VERSION 5.7 ;
  NOWIREEXTENSIONATPIN ON ;
  DIVIDERCHAR "/" ;
  BUSBITCHARS "[]" ;
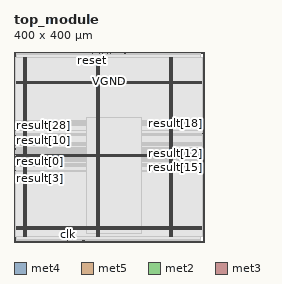
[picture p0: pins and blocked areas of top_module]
MACRO top_module
  CLASS BLOCK ;
  FOREIGN top_module ;
  ORIGIN 0.000 0.000 ;
  SIZE 400.000 BY 400.000 ;
  PIN VGND
    DIRECTION INOUT ;
    USE GROUND ;
    PORT
      LAYER met4 ;
        RECT 24.340 10.640 25.940 389.200 ;
    END
    PORT
      LAYER met4 ;
        RECT 177.940 10.640 179.540 389.200 ;
    END
    PORT
      LAYER met4 ;
        RECT 331.540 10.640 333.140 389.200 ;
    END
    PORT
      LAYER met5 ;
        RECT 5.280 30.030 394.460 31.630 ;
    END
    PORT
      LAYER met5 ;
        RECT 5.280 183.210 394.460 184.810 ;
    END
    PORT
      LAYER met5 ;
        RECT 5.280 336.390 394.460 337.990 ;
    END
  END VGND
  PIN VPWR
    DIRECTION INOUT ;
    USE POWER ;
    PORT
      LAYER met4 ;
        RECT 21.040 10.640 22.640 389.200 ;
    END
    PORT
      LAYER met4 ;
        RECT 174.640 10.640 176.240 389.200 ;
    END
    PORT
      LAYER met4 ;
        RECT 328.240 10.640 329.840 389.200 ;
    END
    PORT
      LAYER met5 ;
        RECT 5.280 26.730 394.460 28.330 ;
    END
    PORT
      LAYER met5 ;
        RECT 5.280 179.910 394.460 181.510 ;
    END
    PORT
      LAYER met5 ;
        RECT 5.280 333.090 394.460 334.690 ;
    END
  END VPWR
  PIN clk
    DIRECTION INPUT ;
    USE SIGNAL ;
    ANTENNAGATEAREA 0.852000 ;
    PORT
      LAYER met2 ;
        RECT 112.790 0.000 113.070 4.000 ;
    END
  END clk
  PIN control
    DIRECTION INPUT ;
    USE SIGNAL ;
    ANTENNAGATEAREA 0.742500 ;
    PORT
      LAYER met2 ;
        RECT 148.210 0.000 148.490 4.000 ;
    END
  END control
  PIN reset
    DIRECTION INPUT ;
    USE SIGNAL ;
    ANTENNAGATEAREA 0.213000 ;
    ANTENNADIFFAREA 0.434700 ;
    PORT
      LAYER met2 ;
        RECT 164.310 396.000 164.590 400.000 ;
    END
  END reset
  PIN result[0]
    DIRECTION OUTPUT ;
    USE SIGNAL ;
    ANTENNADIFFAREA 0.445500 ;
    PORT
      LAYER met3 ;
        RECT 0.000 170.040 4.000 170.640 ;
    END
  END result[0]
  PIN result[10]
    DIRECTION OUTPUT ;
    USE SIGNAL ;
    ANTENNADIFFAREA 0.445500 ;
    PORT
      LAYER met3 ;
        RECT 0.000 197.240 4.000 197.840 ;
    END
  END result[10]
  PIN result[11]
    DIRECTION OUTPUT ;
    USE SIGNAL ;
    ANTENNADIFFAREA 0.445500 ;
    PORT
      LAYER met3 ;
        RECT 0.000 183.640 4.000 184.240 ;
    END
  END result[11]
  PIN result[12]
    DIRECTION OUTPUT ;
    USE SIGNAL ;
    ANTENNADIFFAREA 0.445500 ;
    PORT
      LAYER met3 ;
        RECT 396.000 187.040 400.000 187.640 ;
    END
  END result[12]
  PIN result[13]
    DIRECTION OUTPUT ;
    USE SIGNAL ;
    ANTENNADIFFAREA 0.445500 ;
    PORT
      LAYER met3 ;
        RECT 396.000 190.440 400.000 191.040 ;
    END
  END result[13]
  PIN result[14]
    DIRECTION OUTPUT ;
    USE SIGNAL ;
    ANTENNADIFFAREA 0.445500 ;
    PORT
      LAYER met3 ;
        RECT 396.000 180.240 400.000 180.840 ;
    END
  END result[14]
  PIN result[15]
    DIRECTION OUTPUT ;
    USE SIGNAL ;
    ANTENNADIFFAREA 0.445500 ;
    PORT
      LAYER met3 ;
        RECT 396.000 173.440 400.000 174.040 ;
    END
  END result[15]
  PIN result[16]
    DIRECTION OUTPUT ;
    USE SIGNAL ;
    ANTENNADIFFAREA 0.445500 ;
    PORT
      LAYER met3 ;
        RECT 396.000 183.640 400.000 184.240 ;
    END
  END result[16]
  PIN result[17]
    DIRECTION OUTPUT ;
    USE SIGNAL ;
    ANTENNADIFFAREA 0.445500 ;
    PORT
      LAYER met3 ;
        RECT 396.000 176.840 400.000 177.440 ;
    END
  END result[17]
  PIN result[18]
    DIRECTION OUTPUT ;
    USE SIGNAL ;
    ANTENNADIFFAREA 0.445500 ;
    PORT
      LAYER met3 ;
        RECT 396.000 248.240 400.000 248.840 ;
    END
  END result[18]
  PIN result[19]
    DIRECTION OUTPUT ;
    USE SIGNAL ;
    ANTENNADIFFAREA 0.445500 ;
    PORT
      LAYER met3 ;
        RECT 396.000 251.640 400.000 252.240 ;
    END
  END result[19]
  PIN result[1]
    DIRECTION OUTPUT ;
    USE SIGNAL ;
    ANTENNADIFFAREA 0.445500 ;
    PORT
      LAYER met2 ;
        RECT 144.990 0.000 145.270 4.000 ;
    END
  END result[1]
  PIN result[20]
    DIRECTION OUTPUT ;
    USE SIGNAL ;
    ANTENNADIFFAREA 0.445500 ;
    PORT
      LAYER met3 ;
        RECT 396.000 255.040 400.000 255.640 ;
    END
  END result[20]
  PIN result[21]
    DIRECTION OUTPUT ;
    USE SIGNAL ;
    ANTENNADIFFAREA 0.445500 ;
    PORT
      LAYER met3 ;
        RECT 396.000 227.840 400.000 228.440 ;
    END
  END result[21]
  PIN result[22]
    DIRECTION OUTPUT ;
    USE SIGNAL ;
    ANTENNADIFFAREA 0.795200 ;
    PORT
      LAYER met2 ;
        RECT 231.930 396.000 232.210 400.000 ;
    END
  END result[22]
  PIN result[23]
    DIRECTION OUTPUT ;
    USE SIGNAL ;
    ANTENNADIFFAREA 0.795200 ;
    PORT
      LAYER met2 ;
        RECT 235.150 396.000 235.430 400.000 ;
    END
  END result[23]
  PIN result[24]
    DIRECTION OUTPUT ;
    USE SIGNAL ;
    ANTENNADIFFAREA 0.795200 ;
    PORT
      LAYER met2 ;
        RECT 196.510 396.000 196.790 400.000 ;
    END
  END result[24]
  PIN result[25]
    DIRECTION OUTPUT ;
    USE SIGNAL ;
    ANTENNADIFFAREA 0.795200 ;
    PORT
      LAYER met2 ;
        RECT 202.950 396.000 203.230 400.000 ;
    END
  END result[25]
  PIN result[26]
    DIRECTION OUTPUT ;
    USE SIGNAL ;
    ANTENNADIFFAREA 0.795200 ;
    PORT
      LAYER met2 ;
        RECT 186.850 396.000 187.130 400.000 ;
    END
  END result[26]
  PIN result[27]
    DIRECTION OUTPUT ;
    USE SIGNAL ;
    ANTENNADIFFAREA 0.795200 ;
    PORT
      LAYER met2 ;
        RECT 180.410 396.000 180.690 400.000 ;
    END
  END result[27]
  PIN result[28]
    DIRECTION OUTPUT ;
    USE SIGNAL ;
    ANTENNADIFFAREA 0.445500 ;
    PORT
      LAYER met3 ;
        RECT 0.000 244.840 4.000 245.440 ;
    END
  END result[28]
  PIN result[29]
    DIRECTION OUTPUT ;
    USE SIGNAL ;
    ANTENNADIFFAREA 1.336500 ;
    PORT
      LAYER met3 ;
        RECT 0.000 251.640 4.000 252.240 ;
    END
  END result[29]
  PIN result[2]
    DIRECTION OUTPUT ;
    USE SIGNAL ;
    ANTENNADIFFAREA 0.445500 ;
    PORT
      LAYER met3 ;
        RECT 0.000 159.840 4.000 160.440 ;
    END
  END result[2]
  PIN result[30]
    DIRECTION OUTPUT ;
    USE SIGNAL ;
    ANTENNADIFFAREA 0.445500 ;
    PORT
      LAYER met3 ;
        RECT 0.000 234.640 4.000 235.240 ;
    END
  END result[30]
  PIN result[31]
    DIRECTION OUTPUT ;
    USE SIGNAL ;
    ANTENNADIFFAREA 1.782000 ;
    PORT
      LAYER met3 ;
        RECT 0.000 224.440 4.000 225.040 ;
    END
  END result[31]
  PIN result[3]
    DIRECTION OUTPUT ;
    USE SIGNAL ;
    ANTENNADIFFAREA 0.445500 ;
    PORT
      LAYER met3 ;
        RECT 0.000 149.640 4.000 150.240 ;
    END
  END result[3]
  PIN result[4]
    DIRECTION OUTPUT ;
    USE SIGNAL ;
    ANTENNADIFFAREA 0.445500 ;
    PORT
      LAYER met3 ;
        RECT 0.000 163.240 4.000 163.840 ;
    END
  END result[4]
  PIN result[5]
    DIRECTION OUTPUT ;
    USE SIGNAL ;
    ANTENNADIFFAREA 0.445500 ;
    PORT
      LAYER met3 ;
        RECT 0.000 180.240 4.000 180.840 ;
    END
  END result[5]
  PIN result[6]
    DIRECTION OUTPUT ;
    USE SIGNAL ;
    ANTENNADIFFAREA 0.445500 ;
    PORT
      LAYER met3 ;
        RECT 0.000 176.840 4.000 177.440 ;
    END
  END result[6]
  PIN result[7]
    DIRECTION OUTPUT ;
    USE SIGNAL ;
    ANTENNADIFFAREA 0.445500 ;
    PORT
      LAYER met3 ;
        RECT 0.000 193.840 4.000 194.440 ;
    END
  END result[7]
  PIN result[8]
    DIRECTION OUTPUT ;
    USE SIGNAL ;
    ANTENNADIFFAREA 0.445500 ;
    PORT
      LAYER met3 ;
        RECT 0.000 207.440 4.000 208.040 ;
    END
  END result[8]
  PIN result[9]
    DIRECTION OUTPUT ;
    USE SIGNAL ;
    ANTENNADIFFAREA 0.445500 ;
    PORT
      LAYER met3 ;
        RECT 0.000 204.040 4.000 204.640 ;
    END
  END result[9]
  OBS
      LAYER nwell ;
        RECT 5.330 10.795 394.410 389.150 ;
      LAYER li1 ;
        RECT 5.520 10.795 394.220 389.045 ;
      LAYER met1 ;
        RECT 4.210 10.640 394.220 389.200 ;
      LAYER met2 ;
        RECT 4.230 395.720 164.030 396.000 ;
        RECT 164.870 395.720 180.130 396.000 ;
        RECT 180.970 395.720 186.570 396.000 ;
        RECT 187.410 395.720 196.230 396.000 ;
        RECT 197.070 395.720 202.670 396.000 ;
        RECT 203.510 395.720 231.650 396.000 ;
        RECT 232.490 395.720 234.870 396.000 ;
        RECT 235.710 395.720 392.290 396.000 ;
        RECT 4.230 4.280 392.290 395.720 ;
        RECT 4.230 4.000 112.510 4.280 ;
        RECT 113.350 4.000 144.710 4.280 ;
        RECT 145.550 4.000 147.930 4.280 ;
        RECT 148.770 4.000 392.290 4.280 ;
      LAYER met3 ;
        RECT 3.990 256.040 396.000 389.125 ;
        RECT 3.990 254.640 395.600 256.040 ;
        RECT 3.990 252.640 396.000 254.640 ;
        RECT 4.400 251.240 395.600 252.640 ;
        RECT 3.990 249.240 396.000 251.240 ;
        RECT 3.990 247.840 395.600 249.240 ;
        RECT 3.990 245.840 396.000 247.840 ;
        RECT 4.400 244.440 396.000 245.840 ;
        RECT 3.990 235.640 396.000 244.440 ;
        RECT 4.400 234.240 396.000 235.640 ;
        RECT 3.990 228.840 396.000 234.240 ;
        RECT 3.990 227.440 395.600 228.840 ;
        RECT 3.990 225.440 396.000 227.440 ;
        RECT 4.400 224.040 396.000 225.440 ;
        RECT 3.990 208.440 396.000 224.040 ;
        RECT 4.400 207.040 396.000 208.440 ;
        RECT 3.990 205.040 396.000 207.040 ;
        RECT 4.400 203.640 396.000 205.040 ;
        RECT 3.990 198.240 396.000 203.640 ;
        RECT 4.400 196.840 396.000 198.240 ;
        RECT 3.990 194.840 396.000 196.840 ;
        RECT 4.400 193.440 396.000 194.840 ;
        RECT 3.990 191.440 396.000 193.440 ;
        RECT 3.990 190.040 395.600 191.440 ;
        RECT 3.990 188.040 396.000 190.040 ;
        RECT 3.990 186.640 395.600 188.040 ;
        RECT 3.990 184.640 396.000 186.640 ;
        RECT 4.400 183.240 395.600 184.640 ;
        RECT 3.990 181.240 396.000 183.240 ;
        RECT 4.400 179.840 395.600 181.240 ;
        RECT 3.990 177.840 396.000 179.840 ;
        RECT 4.400 176.440 395.600 177.840 ;
        RECT 3.990 174.440 396.000 176.440 ;
        RECT 3.990 173.040 395.600 174.440 ;
        RECT 3.990 171.040 396.000 173.040 ;
        RECT 4.400 169.640 396.000 171.040 ;
        RECT 3.990 164.240 396.000 169.640 ;
        RECT 4.400 162.840 396.000 164.240 ;
        RECT 3.990 160.840 396.000 162.840 ;
        RECT 4.400 159.440 396.000 160.840 ;
        RECT 3.990 150.640 396.000 159.440 ;
        RECT 4.400 149.240 396.000 150.640 ;
        RECT 3.990 10.715 396.000 149.240 ;
      LAYER met4 ;
        RECT 152.095 17.175 174.240 262.985 ;
        RECT 176.640 17.175 177.540 262.985 ;
        RECT 179.940 17.175 268.345 262.985 ;
  END
END top_module
END LIBRARY

